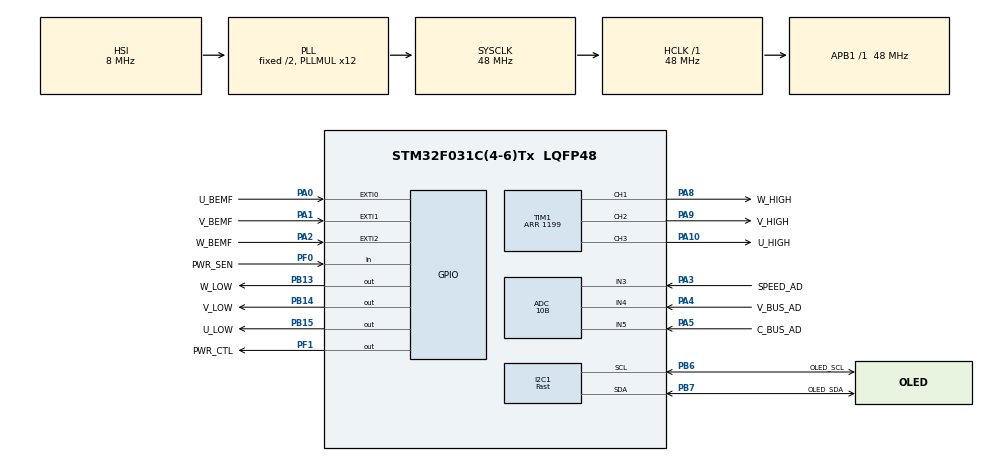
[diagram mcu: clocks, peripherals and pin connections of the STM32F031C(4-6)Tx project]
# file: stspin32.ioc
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ADC.Resolution=ADC_RESOLUTION_10B
ADC.SamplingTime=ADC_SAMPLETIME_13CYCLES_5
Dma.ADC.0.Direction=DMA_PERIPH_TO_MEMORY
Dma.ADC.0.Instance=DMA1_Channel1
Dma.ADC.0.MemDataAlignment=DMA_MDATAALIGN_HALFWORD
Dma.ADC.0.MemInc=DMA_MINC_ENABLE
Dma.ADC.0.Mode=DMA_NORMAL
Dma.ADC.0.PeriphDataAlignment=DMA_PDATAALIGN_HALFWORD
Dma.ADC.0.PeriphInc=DMA_PINC_DISABLE
Dma.ADC.0.Priority=DMA_PRIORITY_MEDIUM
Dma.Request0=ADC
I2C1.I2C_Speed_Mode=I2C_Fast
I2C1.Timing=0x0000020B
Mcu.Family=STM32F0
Mcu.Name=STM32F031C(4-6)Tx
Mcu.Package=LQFP48
NVIC.DMA1_Channel1_IRQn=true\:2\:0\:true\:false\:true\:false\:true
NVIC.EXTI0_1_IRQn=true\:0\:0\:false\:false\:true\:true\:true
NVIC.EXTI2_3_IRQn=true\:0\:0\:false\:false\:true\:true\:true
NVIC.TIM3_IRQn=true\:2\:0\:true\:false\:true\:true\:true
PA0.GPIO_Label=U_BEMF
PA0.Signal=GPXTI0
PA1.GPIO_Label=V_BEMF
PA1.Signal=GPXTI1
PA10.GPIO_Label=U_HIGH
PA10.GPIO_Speed=GPIO_SPEED_FREQ_HIGH
PA10.Signal=S_TIM1_CH3
PA2.GPIO_Label=W_BEMF
PA2.Signal=GPXTI2
PA3.GPIO_Label=SPEED_AD
PA3.Mode=IN3
PA3.Signal=ADC_IN3
PA4.GPIO_Label=V_BUS_AD
PA4.Mode=IN4
PA4.Signal=ADC_IN4
PA5.GPIO_Label=C_BUS_AD
PA5.Mode=IN5
PA5.Signal=ADC_IN5
PA8.GPIO_Label=W_HIGH
PA8.GPIO_Speed=GPIO_SPEED_FREQ_HIGH
PA8.Signal=S_TIM1_CH1
PA9.GPIO_Label=V_HIGH
PA9.GPIO_Speed=GPIO_SPEED_FREQ_HIGH
PA9.Signal=S_TIM1_CH2
PB13.GPIO_Label=W_LOW
PB13.Signal=GPIO_Output
PB14.GPIO_Label=V_LOW
PB14.Signal=GPIO_Output
PB15.GPIO_Label=U_LOW
PB15.Signal=GPIO_Output
PB6.GPIO_Label=OLED_SCL
PB6.Mode=I2C
PB6.Signal=I2C1_SCL
PB7.GPIO_Label=OLED_SDA
PB7.Mode=I2C
PB7.Signal=I2C1_SDA
PF0-OSC_IN.GPIO_Label=PWR_SEN
PF0-OSC_IN.Signal=GPIO_Input
PF1-OSC_OUT.GPIO_Label=PWR_CTL
PF1-OSC_OUT.Signal=GPIO_Output
ProjectManager.HeapSize=0x200
ProjectManager.StackSize=0x400
ProjectManager.TargetToolchain=MDK-ARM V5
RCC.AHBFreq_Value=48000000
RCC.APB1Freq_Value=48000000
RCC.APB1TimFreq_Value=48000000
RCC.HCLKFreq_Value=48000000
RCC.PLLMUL=RCC_PLL_MUL12
RCC.SYSCLKFreq_VALUE=48000000
RCC.SYSCLKSource=RCC_SYSCLKSOURCE_PLLCLK
SH.S_TIM1_CH1.0=TIM1_CH1,PWM Generation1 CH1
SH.S_TIM1_CH2.0=TIM1_CH2,PWM Generation2 CH2
SH.S_TIM1_CH3.0=TIM1_CH3,PWM Generation3 CH3
TIM1.AutoReloadPreload=TIM_AUTORELOAD_PRELOAD_ENABLE
TIM1.Channel-PWM\ Generation1\ CH1=TIM_CHANNEL_1
TIM1.Channel-PWM\ Generation2\ CH2=TIM_CHANNEL_2
TIM1.Channel-PWM\ Generation3\ CH3=TIM_CHANNEL_3
TIM1.ClockDivision=TIM_CLOCKDIVISION_DIV2
TIM1.Period=1199
TIM1.Pulse-PWM\ Generation1\ CH1=100
TIM1.Pulse-PWM\ Generation2\ CH2=200
TIM1.Pulse-PWM\ Generation3\ CH3=300
TIM3.AutoReloadPreload=TIM_AUTORELOAD_PRELOAD_ENABLE
TIM3.Period=999
TIM3.Prescaler=47
VP_TIM1_VS_ClockSourceINT.Mode=Internal
VP_TIM3_VS_ClockSourceINT.Mode=Internal
board=custom

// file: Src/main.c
#include "main.h"

#include "oled.h"
#include "tim.h"
#include "display.h"
#include "ctrl.h"
#include "bldc.h"

/* ctrl.c */
void lock_power(void);
void main_thread(void);

ADC_HandleTypeDef hadc;
DMA_HandleTypeDef hdma_adc;

I2C_HandleTypeDef hi2c1;
TIM_HandleTypeDef htim1;
TIM_HandleTypeDef htim3;

void SystemClock_Config(void);
static void MX_GPIO_Init(void);
static void MX_DMA_Init(void);
static void MX_ADC_Init(void);
static void MX_I2C1_Init(void);
static void MX_TIM1_Init(void);
static void MX_TIM3_Init(void);

void set_pwm_duty(uint16_t duty);
void Motor_SyncRun(uint8_t DIR, uint8_t PHASE);

int main(void)
{
	int i ;
	HAL_Init();

	SystemClock_Config();	//配置时钟

/* 开机短暂延时 */
	HAL_Delay(100);

/* bsp 初始化 */
	MX_GPIO_Init();
	MX_DMA_Init();
	MX_ADC_Init();
	MX_I2C1_Init();
	MX_TIM1_Init();
	MX_TIM3_Init();

/* 电源上锁 */
	lock_power();

/* 初始化定时器 */
	HAL_TIM_Base_Start_IT(&htim3);

/* oled初始化 */
	OLED_Init();
	OLED_Clear();

	set_pwm_duty(100);

	while (1)
	{
		if(isCountTo10ms())
		{
			main_thread();

			i++;
			if(i>5)
				i = 0;
			Motor_SyncRun(MOTOR_DIR_FWD,i);

		}

		if(isCountTo1s())
		{

		}
	}
}

//-------------------------------------------------------------------------
void SystemClock_Config(void)
{
	RCC_OscInitTypeDef RCC_OscInitStruct = {0};
	RCC_ClkInitTypeDef RCC_ClkInitStruct = {0};
	RCC_PeriphCLKInitTypeDef PeriphClkInit = {0};

	/** Initializes the CPU, AHB and APB busses clocks
	*/
	RCC_OscInitStruct.OscillatorType = RCC_OSCILLATORTYPE_HSI|RCC_OSCILLATORTYPE_HSI14;
	RCC_OscInitStruct.HSIState = RCC_HSI_ON;
	RCC_OscInitStruct.HSI14State = RCC_HSI14_ON;
	RCC_OscInitStruct.HSICalibrationValue = RCC_HSICALIBRATION_DEFAULT;
	RCC_OscInitStruct.HSI14CalibrationValue = 16;
	RCC_OscInitStruct.PLL.PLLState = RCC_PLL_ON;
	RCC_OscInitStruct.PLL.PLLSource = RCC_PLLSOURCE_HSI;
	RCC_OscInitStruct.PLL.PLLMUL = RCC_PLL_MUL12;
	RCC_OscInitStruct.PLL.PREDIV = RCC_PREDIV_DIV1;
	if (HAL_RCC_OscConfig(&RCC_OscInitStruct) != HAL_OK)
	{
	Error_Handler();
	}
	/** Initializes the CPU, AHB and APB busses clocks
	*/
	RCC_ClkInitStruct.ClockType = RCC_CLOCKTYPE_HCLK|RCC_CLOCKTYPE_SYSCLK
							  |RCC_CLOCKTYPE_PCLK1;
	RCC_ClkInitStruct.SYSCLKSource = RCC_SYSCLKSOURCE_PLLCLK;
	RCC_ClkInitStruct.AHBCLKDivider = RCC_SYSCLK_DIV1;
	RCC_ClkInitStruct.APB1CLKDivider = RCC_HCLK_DIV1;

	if (HAL_RCC_ClockConfig(&RCC_ClkInitStruct, FLASH_LATENCY_1) != HAL_OK)
	{
		Error_Handler();
	}
		PeriphClkInit.PeriphClockSelection = RCC_PERIPHCLK_I2C1;
		PeriphClkInit.I2c1ClockSelection = RCC_I2C1CLKSOURCE_HSI;
	if (HAL_RCCEx_PeriphCLKConfig(&PeriphClkInit) != HAL_OK)
	{
		Error_Handler();
	}
}

static void MX_ADC_Init(void)
{

  ADC_ChannelConfTypeDef sConfig = {0};

  /** Configure the global features of the ADC (Clock, Resolution, Data Alignment and number of conversion)
  */
  hadc.Instance = ADC1;
  hadc.Init.ClockPrescaler = ADC_CLOCK_ASYNC_DIV1;
  hadc.Init.Resolution = ADC_RESOLUTION_10B;
  hadc.Init.DataAlign = ADC_DATAALIGN_RIGHT;
  hadc.Init.ScanConvMode = ADC_SCAN_DIRECTION_FORWARD;
  hadc.Init.EOCSelection = ADC_EOC_SINGLE_CONV;
  hadc.Init.LowPowerAutoWait = DISABLE;
  hadc.Init.LowPowerAutoPowerOff = DISABLE;
  hadc.Init.ContinuousConvMode = DISABLE;
  hadc.Init.DiscontinuousConvMode = DISABLE;
  hadc.Init.ExternalTrigConv = ADC_SOFTWARE_START;
  hadc.Init.ExternalTrigConvEdge = ADC_EXTERNALTRIGCONVEDGE_NONE;
  hadc.Init.DMAContinuousRequests = DISABLE;
  hadc.Init.Overrun = ADC_OVR_DATA_PRESERVED;
  if (HAL_ADC_Init(&hadc) != HAL_OK)
  {
    Error_Handler();
  }
  /** Configure for the selected ADC regular channel to be converted.
  */
  sConfig.Channel = ADC_CHANNEL_3;
  sConfig.Rank = ADC_RANK_CHANNEL_NUMBER;
  sConfig.SamplingTime = ADC_SAMPLETIME_13CYCLES_5;
  if (HAL_ADC_ConfigChannel(&hadc, &sConfig) != HAL_OK)
  {
    Error_Handler();
  }
  /** Configure for the selected ADC regular channel to be converted.
  */
  sConfig.Channel = ADC_CHANNEL_4;
  if (HAL_ADC_ConfigChannel(&hadc, &sConfig) != HAL_OK)
  {
    Error_Handler();
  }
  /** Configure for the selected ADC regular channel to be converted.
  */
  sConfig.Channel = ADC_CHANNEL_5;
  if (HAL_ADC_ConfigChannel(&hadc, &sConfig) != HAL_OK)
  {
    Error_Handler();
  }

}

static void MX_I2C1_Init(void)
{

  hi2c1.Instance = I2C1;
  hi2c1.Init.Timing = 0x0000020B;
  hi2c1.Init.OwnAddress1 = 0;
  hi2c1.Init.AddressingMode = I2C_ADDRESSINGMODE_7BIT;
  hi2c1.Init.DualAddressMode = I2C_DUALADDRESS_DISABLE;
  hi2c1.Init.OwnAddress2 = 0;
  hi2c1.Init.OwnAddress2Masks = I2C_OA2_NOMASK;
  hi2c1.Init.GeneralCallMode = I2C_GENERALCALL_DISABLE;
  hi2c1.Init.NoStretchMode = I2C_NOSTRETCH_DISABLE;
  if (HAL_I2C_Init(&hi2c1) != HAL_OK)
  {
    Error_Handler();
  }
  /** Configure Analogue filter
  */
  if (HAL_I2CEx_ConfigAnalogFilter(&hi2c1, I2C_ANALOGFILTER_ENABLE) != HAL_OK)
  {
    Error_Handler();
  }
  /** Configure Digital filter
  */
  if (HAL_I2CEx_ConfigDigitalFilter(&hi2c1, 0) != HAL_OK)
  {
    Error_Handler();
  }

}

static void MX_TIM1_Init(void)
{

  TIM_ClockConfigTypeDef sClockSourceConfig = {0};
  TIM_MasterConfigTypeDef sMasterConfig = {0};
  TIM_OC_InitTypeDef sConfigOC = {0};
  TIM_BreakDeadTimeConfigTypeDef sBreakDeadTimeConfig = {0};

  htim1.Instance = TIM1;
  htim1.Init.Prescaler = 0;
  htim1.Init.CounterMode = TIM_COUNTERMODE_UP;
  htim1.Init.Period = 1199;
  htim1.Init.ClockDivision = TIM_CLOCKDIVISION_DIV2;
  htim1.Init.RepetitionCounter = 0;
  htim1.Init.AutoReloadPreload = TIM_AUTORELOAD_PRELOAD_ENABLE;
  if (HAL_TIM_Base_Init(&htim1) != HAL_OK)
  {
    Error_Handler();
  }
  sClockSourceConfig.ClockSource = TIM_CLOCKSOURCE_INTERNAL;
  if (HAL_TIM_ConfigClockSource(&htim1, &sClockSourceConfig) != HAL_OK)
  {
    Error_Handler();
  }
  if (HAL_TIM_PWM_Init(&htim1) != HAL_OK)
  {
    Error_Handler();
  }
  sMasterConfig.MasterOutputTrigger = TIM_TRGO_RESET;
  sMasterConfig.MasterSlaveMode = TIM_MASTERSLAVEMODE_DISABLE;
  if (HAL_TIMEx_MasterConfigSynchronization(&htim1, &sMasterConfig) != HAL_OK)
  {
    Error_Handler();
  }
  sConfigOC.OCMode = TIM_OCMODE_PWM1;
  sConfigOC.Pulse = 100;
  sConfigOC.OCPolarity = TIM_OCPOLARITY_HIGH;
  sConfigOC.OCNPolarity = TIM_OCNPOLARITY_HIGH;
  sConfigOC.OCFastMode = TIM_OCFAST_DISABLE;
  sConfigOC.OCIdleState = TIM_OCIDLESTATE_RESET;
  sConfigOC.OCNIdleState = TIM_OCNIDLESTATE_RESET;
  if (HAL_TIM_PWM_ConfigChannel(&htim1, &sConfigOC, TIM_CHANNEL_1) != HAL_OK)
  {
    Error_Handler();
  }
  sConfigOC.Pulse = 200;
  if (HAL_TIM_PWM_ConfigChannel(&htim1, &sConfigOC, TIM_CHANNEL_2) != HAL_OK)
  {
    Error_Handler();
  }
  sConfigOC.Pulse = 300;
  if (HAL_TIM_PWM_ConfigChannel(&htim1, &sConfigOC, TIM_CHANNEL_3) != HAL_OK)
  {
    Error_Handler();
  }
  sBreakDeadTimeConfig.OffStateRunMode = TIM_OSSR_DISABLE;
  sBreakDeadTimeConfig.OffStateIDLEMode = TIM_OSSI_DISABLE;
  sBreakDeadTimeConfig.LockLevel = TIM_LOCKLEVEL_OFF;
  sBreakDeadTimeConfig.DeadTime = 0;
  sBreakDeadTimeConfig.BreakState = TIM_BREAK_DISABLE;
  sBreakDeadTimeConfig.BreakPolarity = TIM_BREAKPOLARITY_HIGH;
  sBreakDeadTimeConfig.AutomaticOutput = TIM_AUTOMATICOUTPUT_DISABLE;
  if (HAL_TIMEx_ConfigBreakDeadTime(&htim1, &sBreakDeadTimeConfig) != HAL_OK)
  {
    Error_Handler();
  }
  HAL_TIM_MspPostInit(&htim1);

}

static void MX_TIM3_Init(void)
{

  TIM_ClockConfigTypeDef sClockSourceConfig = {0};
  TIM_MasterConfigTypeDef sMasterConfig = {0};

  htim3.Instance = TIM3;
  htim3.Init.Prescaler = 47;
  htim3.Init.CounterMode = TIM_COUNTERMODE_UP;
  htim3.Init.Period = 999;
  htim3.Init.ClockDivision = TIM_CLOCKDIVISION_DIV1;
  htim3.Init.AutoReloadPreload = TIM_AUTORELOAD_PRELOAD_ENABLE;
  if (HAL_TIM_Base_Init(&htim3) != HAL_OK)
  {
    Error_Handler();
  }
  sClockSourceConfig.ClockSource = TIM_CLOCKSOURCE_INTERNAL;
  if (HAL_TIM_ConfigClockSource(&htim3, &sClockSourceConfig) != HAL_OK)
  {
    Error_Handler();
  }
  sMasterConfig.MasterOutputTrigger = TIM_TRGO_RESET;
  sMasterConfig.MasterSlaveMode = TIM_MASTERSLAVEMODE_DISABLE;
  if (HAL_TIMEx_MasterConfigSynchronization(&htim3, &sMasterConfig) != HAL_OK)
  {
    Error_Handler();
  }

}

static void MX_DMA_Init(void)
{
  /* DMA controller clock enable */
  __HAL_RCC_DMA1_CLK_ENABLE();

  /* DMA interrupt init */
  /* DMA1_Channel1_IRQn interrupt configuration */
  HAL_NVIC_SetPriority(DMA1_Channel1_IRQn, 2, 0);
  HAL_NVIC_EnableIRQ(DMA1_Channel1_IRQn);

}

static void MX_GPIO_Init(void)
{
  GPIO_InitTypeDef GPIO_InitStruct = {0};

  /* GPIO Ports Clock Enable */
  __HAL_RCC_GPIOF_CLK_ENABLE();
  __HAL_RCC_GPIOA_CLK_ENABLE();
  __HAL_RCC_GPIOB_CLK_ENABLE();

  /*Configure GPIO pin Output Level */
  HAL_GPIO_WritePin(PWR_CTL_GPIO_Port, PWR_CTL_Pin|OC_SEL_Pin, GPIO_PIN_RESET);
  /*Configure GPIO pin Output Level */
  HAL_GPIO_WritePin(GPIOB, W_LOW_Pin|V_LOW_Pin|U_LOW_Pin, GPIO_PIN_RESET);
  HAL_GPIO_WritePin(GPIOF, GPIO_PIN_6|GPIO_PIN_7, GPIO_PIN_SET);
  /*Configure GPIO pin : PWR_SEN_Pin */
  GPIO_InitStruct.Pin = PWR_SEN_Pin;
  GPIO_InitStruct.Mode = GPIO_MODE_INPUT;
  GPIO_InitStruct.Pull = GPIO_NOPULL;
  HAL_GPIO_Init(PWR_SEN_GPIO_Port, &GPIO_InitStruct);

  /*Configure GPIO pin : PWR_CTL_Pin */
  GPIO_InitStruct.Pin = PWR_CTL_Pin;
  GPIO_InitStruct.Mode = GPIO_MODE_OUTPUT_PP;
  GPIO_InitStruct.Pull = GPIO_NOPULL;
  GPIO_InitStruct.Speed = GPIO_SPEED_FREQ_LOW;
  HAL_GPIO_Init(PWR_CTL_GPIO_Port, &GPIO_InitStruct);

  /*Configure GPIO pin : OC_SEL_Pin */
  GPIO_InitStruct.Pin = OC_SEL_Pin;
  GPIO_InitStruct.Mode = GPIO_MODE_OUTPUT_PP;
  GPIO_InitStruct.Pull = GPIO_NOPULL;
  GPIO_InitStruct.Speed = GPIO_SPEED_FREQ_LOW;
  HAL_GPIO_Init(OC_SEL_GPIO_Port, &GPIO_InitStruct);

    GPIO_InitStruct.Pin = GPIO_PIN_6|GPIO_PIN_7;
  GPIO_InitStruct.Mode = GPIO_MODE_OUTPUT_PP;
  GPIO_InitStruct.Pull = GPIO_NOPULL;
  GPIO_InitStruct.Speed = GPIO_SPEED_FREQ_LOW;
  HAL_GPIO_Init(GPIOF, &GPIO_InitStruct);

  /*Configure GPIO pins : U_BEMF_Pin V_BEMF_Pin W_BEMF_Pin */
  GPIO_InitStruct.Pin = U_BEMF_Pin|V_BEMF_Pin|W_BEMF_Pin;
  GPIO_InitStruct.Mode = GPIO_MODE_IT_RISING_FALLING;
  GPIO_InitStruct.Pull = GPIO_PULLUP;
  HAL_GPIO_Init(GPIOA, &GPIO_InitStruct);

  /*Configure GPIO pins : W_LOW_Pin V_LOW_Pin U_LOW_Pin */
  GPIO_InitStruct.Pin = W_LOW_Pin|V_LOW_Pin|U_LOW_Pin;
  GPIO_InitStruct.Mode = GPIO_MODE_OUTPUT_PP;
  GPIO_InitStruct.Pull = GPIO_NOPULL;
  GPIO_InitStruct.Speed = GPIO_SPEED_FREQ_HIGH;
  HAL_GPIO_Init(GPIOB, &GPIO_InitStruct);

  /* EXTI interrupt init*/
  HAL_NVIC_SetPriority(EXTI0_1_IRQn, 0, 0);
  HAL_NVIC_EnableIRQ(EXTI0_1_IRQn);

  HAL_NVIC_SetPriority(EXTI2_3_IRQn, 0, 0);
  HAL_NVIC_EnableIRQ(EXTI2_3_IRQn);

}

void Error_Handler(void)
{
}

/************************ (C) COPYRIGHT STMicroelectronics *****END OF FILE****/
